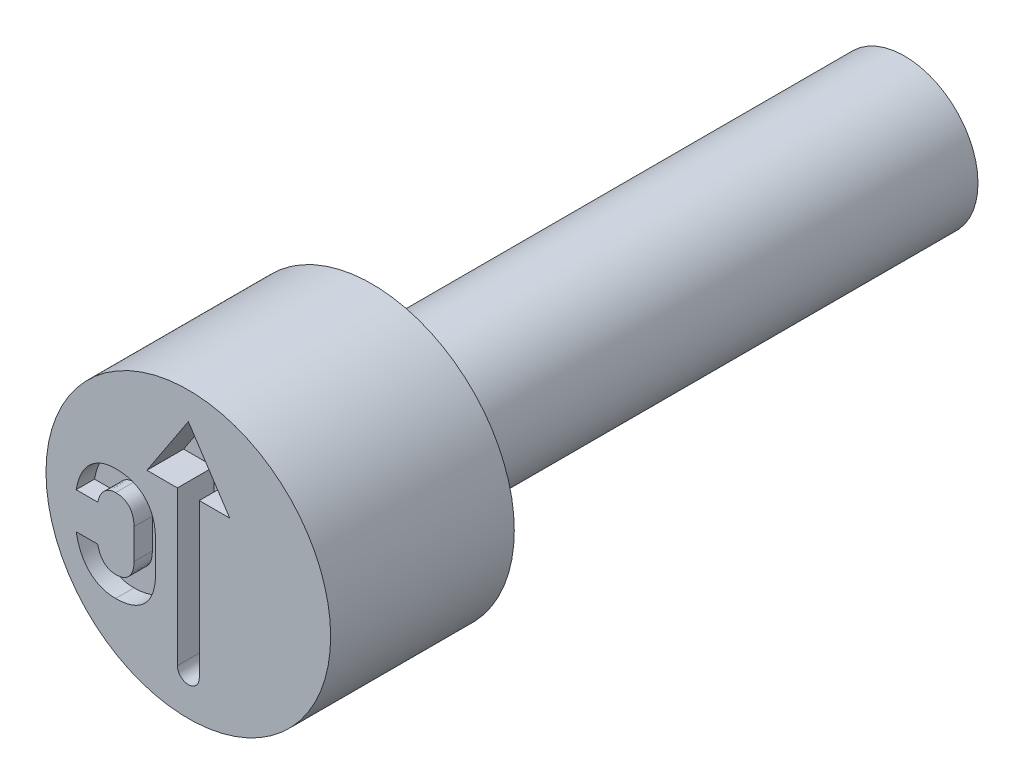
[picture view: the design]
ISO-10303-21;
HEADER;
FILE_DESCRIPTION(('STEP AP214'),'2;1');
FILE_NAME('part.step','',(''),(''),'','','');
FILE_SCHEMA(('AUTOMOTIVE_DESIGN { 1 0 10303 214 1 1 1 1 }'));
ENDSEC;
DATA;
#1=APPLICATION_CONTEXT('core data for automotive mechanical design processes');
#2=APPLICATION_PROTOCOL_DEFINITION('international standard','automotive_design',2000,#1);
#3=PRODUCT_CONTEXT('',#1,'mechanical');
#4=PRODUCT('Part','Part','',(#3));
#5=PRODUCT_RELATED_PRODUCT_CATEGORY('part','',(#4));
#6=PRODUCT_DEFINITION_FORMATION('','',#4);
#7=PRODUCT_DEFINITION_CONTEXT('part definition',#1,'design');
#8=PRODUCT_DEFINITION('design','',#6,#7);
#9=PRODUCT_DEFINITION_SHAPE('','',#8);
#10=(LENGTH_UNIT() NAMED_UNIT(*) SI_UNIT(.MILLI.,.METRE.));
#11=(NAMED_UNIT(*) PLANE_ANGLE_UNIT() SI_UNIT($,.RADIAN.));
#12=(NAMED_UNIT(*) SI_UNIT($,.STERADIAN.) SOLID_ANGLE_UNIT());
#13=UNCERTAINTY_MEASURE_WITH_UNIT(LENGTH_MEASURE(1.E-05),#10,'distance_accuracy_value','');
#14=(GEOMETRIC_REPRESENTATION_CONTEXT(3) GLOBAL_UNCERTAINTY_ASSIGNED_CONTEXT((#13)) GLOBAL_UNIT_ASSIGNED_CONTEXT((#10,
#11,#12)) REPRESENTATION_CONTEXT('',''));
#15=CARTESIAN_POINT('',(0.,0.,0.));
#16=DIRECTION('',(0.,0.,1.));
#17=DIRECTION('',(1.,0.,0.));
#18=AXIS2_PLACEMENT_3D('',#15,#16,#17);
#19=CARTESIAN_POINT('',(0.,0.799999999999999,-2.));
#20=DIRECTION('',(0.,0.,1.));
#21=DIRECTION('',(1.,0.,0.));
#22=AXIS2_PLACEMENT_3D('',#19,#20,#21);
#23=PLANE('',#22);
#24=CARTESIAN_POINT('',(0.,0.,-2.));
#25=DIRECTION('',(0.,0.,1.));
#26=DIRECTION('',(1.,0.,0.));
#27=AXIS2_PLACEMENT_3D('',#24,#25,#26);
#28=CIRCLE('',#27,1.55);
#29=CARTESIAN_POINT('',(1.55,0.,-2.));
#30=VERTEX_POINT('',#29);
#31=EDGE_CURVE('E11',#30,#30,#28,.T.);
#32=ORIENTED_EDGE('',*,*,#31,.F.);
#33=EDGE_LOOP('',(#32));
#34=FACE_BOUND('',#33,.T.);
#35=CARTESIAN_POINT('',(0.,0.,-2.));
#36=DIRECTION('',(0.,0.,1.));
#37=DIRECTION('',(1.,0.,0.));
#38=AXIS2_PLACEMENT_3D('',#35,#36,#37);
#39=CIRCLE('',#38,0.799999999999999);
#40=CARTESIAN_POINT('',(0.799999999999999,0.,-2.));
#41=VERTEX_POINT('',#40);
#42=EDGE_CURVE('E262',#41,#41,#39,.T.);
#43=ORIENTED_EDGE('',*,*,#42,.T.);
#44=EDGE_LOOP('',(#43));
#45=FACE_BOUND('',#44,.T.);
#46=ADVANCED_FACE('F34',(#34,#45),#23,.F.);
#47=CARTESIAN_POINT('',(0.,0.,-0.403888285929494));
#48=DIRECTION('',(0.,0.,1.));
#49=DIRECTION('',(1.,0.,0.));
#50=AXIS2_PLACEMENT_3D('',#47,#48,#49);
#51=CYLINDRICAL_SURFACE('',#50,1.55);
#52=CARTESIAN_POINT('',(0.,0.,0.));
#53=DIRECTION('',(0.,0.,1.));
#54=DIRECTION('',(1.,0.,0.));
#55=AXIS2_PLACEMENT_3D('',#52,#53,#54);
#56=CIRCLE('',#55,1.55);
#57=CARTESIAN_POINT('',(1.55,0.,0.));
#58=VERTEX_POINT('',#57);
#59=EDGE_CURVE('E41',#58,#58,#56,.T.);
#60=ORIENTED_EDGE('',*,*,#59,.F.);
#61=EDGE_LOOP('',(#60));
#62=FACE_BOUND('',#61,.T.);
#63=ORIENTED_EDGE('',*,*,#31,.T.);
#64=EDGE_LOOP('',(#63));
#65=FACE_BOUND('',#64,.T.);
#66=ADVANCED_FACE('F247',(#62,#65),#51,.T.);
#67=CARTESIAN_POINT('',(0.,1.55,0.));
#68=DIRECTION('',(0.,0.,-1.));
#69=DIRECTION('',(-1.,0.,0.));
#70=AXIS2_PLACEMENT_3D('',#67,#68,#69);
#71=PLANE('',#70);
#72=CARTESIAN_POINT('',(-0.791430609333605,-0.812471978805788,0.));
#73=CARTESIAN_POINT('',(-0.780258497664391,-0.812351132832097,0.));
#74=CARTESIAN_POINT('',(-0.758212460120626,-0.812112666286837,0.));
#75=CARTESIAN_POINT('',(-0.725795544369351,-0.809631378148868,0.));
#76=CARTESIAN_POINT('',(-0.694521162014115,-0.805483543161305,0.));
#77=CARTESIAN_POINT('',(-0.66455986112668,-0.799634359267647,0.));
#78=CARTESIAN_POINT('',(-0.635828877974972,-0.792255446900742,0.));
#79=CARTESIAN_POINT('',(-0.608205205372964,-0.783533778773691,0.));
#80=CARTESIAN_POINT('',(-0.581954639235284,-0.772736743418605,0.));
#81=CARTESIAN_POINT('',(-0.556822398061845,-0.760492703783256,0.));
#82=CARTESIAN_POINT('',(-0.53316239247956,-0.746634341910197,0.));
#83=CARTESIAN_POINT('',(-0.511024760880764,-0.731046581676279,0.));
#84=CARTESIAN_POINT('',(-0.490189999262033,-0.714218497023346,0.));
#85=CARTESIAN_POINT('',(-0.470816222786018,-0.695812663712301,0.));
#86=CARTESIAN_POINT('',(-0.452923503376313,-0.675936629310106,0.));
#87=CARTESIAN_POINT('',(-0.436410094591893,-0.65456836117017,0.));
#88=CARTESIAN_POINT('',(-0.421615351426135,-0.631571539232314,0.));
#89=CARTESIAN_POINT('',(-0.408081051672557,-0.607256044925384,0.));
#90=CARTESIAN_POINT('',(-0.396039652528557,-0.58155541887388,0.));
#91=CARTESIAN_POINT('',(-0.385876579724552,-0.55434699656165,0.));
#92=CARTESIAN_POINT('',(-0.377065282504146,-0.525931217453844,0.));
#93=CARTESIAN_POINT('',(-0.36969451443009,-0.496312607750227,0.));
#94=CARTESIAN_POINT('',(-0.364051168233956,-0.465356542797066,0.));
#95=CARTESIAN_POINT('',(-0.360289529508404,-0.433086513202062,0.));
#96=CARTESIAN_POINT('',(-0.357681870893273,-0.39947214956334,0.));
#97=CARTESIAN_POINT('',(-0.357466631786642,-0.376610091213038,0.));
#98=CARTESIAN_POINT('',(-0.357356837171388,-0.364948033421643,0.));
#99=B_SPLINE_CURVE_WITH_KNOTS('',3,(#72,#73,#74,#75,#76,#77,#78,#79,#80,#81,#82,#83,#84,#85,#86,
#87,#88,#89,#90,#91,#92,#93,#94,#95,#96,#97,#98),.UNSPECIFIED.,.F.,.F.,(4,1,1,1,1,1,1,1,1,1,1,1,
1,1,1,1,1,1,1,1,1,1,1,1,4),(0.,0.04725989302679,0.0932584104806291,0.137448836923,
0.180669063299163,0.222325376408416,0.262898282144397,0.303117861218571,0.342294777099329,
0.381096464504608,0.418984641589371,0.456742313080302,0.494310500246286,0.531916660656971,
0.569787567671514,0.608434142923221,0.647492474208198,0.687453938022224,0.728384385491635,
0.770272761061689,0.813266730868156,0.85743965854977,0.903297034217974,0.950671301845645,1.),.UNSPECIFIED.);
#100=CARTESIAN_POINT('',(-0.791430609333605,-0.812471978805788,0.));
#101=VERTEX_POINT('',#100);
#102=CARTESIAN_POINT('',(-0.357356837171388,-0.364948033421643,0.));
#103=VERTEX_POINT('',#102);
#104=EDGE_CURVE('E400',#101,#103,#99,.T.);
#105=ORIENTED_EDGE('',*,*,#104,.F.);
#106=CARTESIAN_POINT('',(-1.22134705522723,-0.397962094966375,0.));
#107=CARTESIAN_POINT('',(-1.2171676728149,-0.419166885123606,0.));
#108=CARTESIAN_POINT('',(-1.20904219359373,-0.460392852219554,0.));
#109=CARTESIAN_POINT('',(-1.19078283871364,-0.519101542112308,0.));
#110=CARTESIAN_POINT('',(-1.16828133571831,-0.573041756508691,0.));
#111=CARTESIAN_POINT('',(-1.14150329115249,-0.62213258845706,0.));
#112=CARTESIAN_POINT('',(-1.11028545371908,-0.665888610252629,0.));
#113=CARTESIAN_POINT('',(-1.07537476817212,-0.704473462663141,0.));
#114=CARTESIAN_POINT('',(-1.03647621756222,-0.737561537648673,0.));
#115=CARTESIAN_POINT('',(-0.993669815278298,-0.764820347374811,0.));
#116=CARTESIAN_POINT('',(-0.947448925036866,-0.786249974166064,0.));
#117=CARTESIAN_POINT('',(-0.898066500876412,-0.80129948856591,0.));
#118=CARTESIAN_POINT('',(-0.845777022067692,-0.811035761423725,0.));
#119=CARTESIAN_POINT('',(-0.809816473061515,-0.811986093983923,0.));
#120=CARTESIAN_POINT('',(-0.791430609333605,-0.812471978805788,0.));
#121=B_SPLINE_CURVE_WITH_KNOTS('',3,(#106,#107,#108,#109,#110,#111,#112,#113,#114,#115,#116,
#117,#118,#119,#120),.UNSPECIFIED.,.F.,.F.,(4,1,1,1,1,1,1,1,1,1,1,1,4),(0.,0.0988237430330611,
0.192131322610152,0.28071953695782,0.365844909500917,0.447392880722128,0.52606487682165,
0.603327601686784,0.680299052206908,0.757555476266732,0.835645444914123,0.915969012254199,1.),.UNSPECIFIED.);
#122=CARTESIAN_POINT('',(-1.22134705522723,-0.397962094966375,0.));
#123=VERTEX_POINT('',#122);
#124=EDGE_CURVE('E48',#123,#101,#121,.T.);
#125=ORIENTED_EDGE('',*,*,#124,.F.);
#126=DIRECTION('',(-1.,0.,0.));
#127=VECTOR('',#126,1.);
#128=CARTESIAN_POINT('',(-0.987069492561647,-0.397962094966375,0.));
#129=LINE('',#128,#127);
#130=CARTESIAN_POINT('',(-0.987069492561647,-0.397962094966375,0.));
#131=VERTEX_POINT('',#130);
#132=EDGE_CURVE('E185',#131,#123,#129,.T.);
#133=ORIENTED_EDGE('',*,*,#132,.F.);
#134=CARTESIAN_POINT('',(-0.791430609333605,-0.586264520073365,0.));
#135=CARTESIAN_POINT('',(-0.799513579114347,-0.585946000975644,0.));
#136=CARTESIAN_POINT('',(-0.815367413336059,-0.585321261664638,0.));
#137=CARTESIAN_POINT('',(-0.838528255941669,-0.581496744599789,0.));
#138=CARTESIAN_POINT('',(-0.86033493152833,-0.57444835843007,0.));
#139=CARTESIAN_POINT('',(-0.880934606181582,-0.564951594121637,0.));
#140=CARTESIAN_POINT('',(-0.900176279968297,-0.552681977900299,0.));
#141=CARTESIAN_POINT('',(-0.917511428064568,-0.537522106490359,0.));
#142=CARTESIAN_POINT('',(-0.933658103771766,-0.520265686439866,0.));
#143=CARTESIAN_POINT('',(-0.948029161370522,-0.500350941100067,0.));
#144=CARTESIAN_POINT('',(-0.960768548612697,-0.47806525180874,0.));
#145=CARTESIAN_POINT('',(-0.971422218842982,-0.453400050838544,0.));
#146=CARTESIAN_POINT('',(-0.980669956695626,-0.426630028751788,0.));
#147=CARTESIAN_POINT('',(-0.984892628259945,-0.407713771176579,0.));
#148=CARTESIAN_POINT('',(-0.987069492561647,-0.397962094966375,0.));
#149=B_SPLINE_CURVE_WITH_KNOTS('',3,(#134,#135,#136,#137,#138,#139,#140,#141,#142,#143,#144,
#145,#146,#147,#148),.UNSPECIFIED.,.F.,.F.,(4,1,1,1,1,1,1,1,1,1,1,1,4),(0.,0.0817564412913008,
0.160356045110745,0.236478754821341,0.312819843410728,0.389192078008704,0.466352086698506,
0.545094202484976,0.627698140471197,0.714093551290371,0.80415108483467,0.89903630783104,1.),.UNSPECIFIED.);
#150=CARTESIAN_POINT('',(-0.791430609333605,-0.586264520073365,0.));
#151=VERTEX_POINT('',#150);
#152=EDGE_CURVE('E188',#151,#131,#149,.T.);
#153=ORIENTED_EDGE('',*,*,#152,.F.);
#154=CARTESIAN_POINT('',(-0.591634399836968,-0.364948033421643,0.));
#155=CARTESIAN_POINT('',(-0.591898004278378,-0.376212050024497,0.));
#156=CARTESIAN_POINT('',(-0.592408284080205,-0.398016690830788,0.));
#157=CARTESIAN_POINT('',(-0.59682906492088,-0.429429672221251,0.));
#158=CARTESIAN_POINT('',(-0.604142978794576,-0.4583247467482,0.));
#159=CARTESIAN_POINT('',(-0.614290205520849,-0.484652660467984,0.));
#160=CARTESIAN_POINT('',(-0.62761931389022,-0.508037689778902,0.));
#161=CARTESIAN_POINT('',(-0.6434486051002,-0.528668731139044,0.));
#162=CARTESIAN_POINT('',(-0.661869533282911,-0.546495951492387,0.));
#163=CARTESIAN_POINT('',(-0.683168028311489,-0.561000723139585,0.));
#164=CARTESIAN_POINT('',(-0.706927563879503,-0.572346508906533,0.));
#165=CARTESIAN_POINT('',(-0.733057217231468,-0.580321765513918,0.));
#166=CARTESIAN_POINT('',(-0.76148736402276,-0.585328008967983,0.));
#167=CARTESIAN_POINT('',(-0.781219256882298,-0.585945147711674,0.));
#168=CARTESIAN_POINT('',(-0.791430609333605,-0.586264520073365,0.));
#169=B_SPLINE_CURVE_WITH_KNOTS('',3,(#154,#155,#156,#157,#158,#159,#160,#161,#162,#163,#164,
#165,#166,#167,#168),.UNSPECIFIED.,.F.,.F.,(4,1,1,1,1,1,1,1,1,1,1,1,4),(0.,0.0997433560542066,
0.193081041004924,0.28029932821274,0.363302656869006,0.442209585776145,0.517891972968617,
0.592965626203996,0.668275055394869,0.745143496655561,0.825309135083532,0.909596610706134,1.),.UNSPECIFIED.);
#170=CARTESIAN_POINT('',(-0.591634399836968,-0.364948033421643,0.));
#171=VERTEX_POINT('',#170);
#172=EDGE_CURVE('E348',#171,#151,#169,.T.);
#173=ORIENTED_EDGE('',*,*,#172,.F.);
#174=DIRECTION('',(0.,-1.,0.));
#175=VECTOR('',#174,1.);
#176=CARTESIAN_POINT('',(-0.591634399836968,-0.0357856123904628,0.));
#177=LINE('',#176,#175);
#178=CARTESIAN_POINT('',(-0.591634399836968,-0.0357856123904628,0.));
#179=VERTEX_POINT('',#178);
#180=EDGE_CURVE('E356',#179,#171,#177,.T.);
#181=ORIENTED_EDGE('',*,*,#180,.F.);
#182=CARTESIAN_POINT('',(-0.791430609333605,0.186264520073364,0.));
#183=CARTESIAN_POINT('',(-0.781226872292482,0.185907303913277,0.));
#184=CARTESIAN_POINT('',(-0.761523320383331,0.185217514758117,0.));
#185=CARTESIAN_POINT('',(-0.732979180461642,0.180723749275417,0.));
#186=CARTESIAN_POINT('',(-0.706978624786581,0.172258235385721,0.));
#187=CARTESIAN_POINT('',(-0.683158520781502,0.161027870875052,0.));
#188=CARTESIAN_POINT('',(-0.661879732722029,0.146482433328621,0.));
#189=CARTESIAN_POINT('',(-0.643370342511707,0.128650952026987,0.));
#190=CARTESIAN_POINT('',(-0.627621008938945,0.107775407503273,0.));
#191=CARTESIAN_POINT('',(-0.614349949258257,0.0842150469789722,0.));
#192=CARTESIAN_POINT('',(-0.604088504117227,0.0577700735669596,0.));
#193=CARTESIAN_POINT('',(-0.596868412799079,0.0287667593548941,0.));
#194=CARTESIAN_POINT('',(-0.592400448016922,-0.00271483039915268,0.));
#195=CARTESIAN_POINT('',(-0.591895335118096,-0.0245208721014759,0.));
#196=CARTESIAN_POINT('',(-0.591634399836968,-0.0357856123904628,0.));
#197=B_SPLINE_CURVE_WITH_KNOTS('',3,(#182,#183,#184,#185,#186,#187,#188,#189,#190,#191,#192,
#193,#194,#195,#196),.UNSPECIFIED.,.F.,.F.,(4,1,1,1,1,1,1,1,1,1,1,1,4),(0.,0.0902231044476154,
0.174222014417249,0.25444494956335,0.331160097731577,0.406319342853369,0.481243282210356,
0.557346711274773,0.636723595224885,0.719561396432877,0.807304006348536,0.900455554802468,1.),.UNSPECIFIED.);
#198=CARTESIAN_POINT('',(-0.791430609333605,0.186264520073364,0.));
#199=VERTEX_POINT('',#198);
#200=EDGE_CURVE('E362',#199,#179,#197,.T.);
#201=ORIENTED_EDGE('',*,*,#200,.F.);
#202=CARTESIAN_POINT('',(-0.987069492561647,-0.00179335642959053,0.));
#203=CARTESIAN_POINT('',(-0.984706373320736,0.00779221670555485,0.));
#204=CARTESIAN_POINT('',(-0.980107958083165,0.0264448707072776,0.));
#205=CARTESIAN_POINT('',(-0.970640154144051,0.0529798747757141,0.));
#206=CARTESIAN_POINT('',(-0.959874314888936,0.0775584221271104,0.));
#207=CARTESIAN_POINT('',(-0.946707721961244,0.0995949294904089,0.));
#208=CARTESIAN_POINT('',(-0.932374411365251,0.11962144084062,0.));
#209=CARTESIAN_POINT('',(-0.916209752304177,0.136971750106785,0.));
#210=CARTESIAN_POINT('',(-0.898567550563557,0.151933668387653,0.));
#211=CARTESIAN_POINT('',(-0.879584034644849,0.164308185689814,0.));
#212=CARTESIAN_POINT('',(-0.859310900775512,0.17439320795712,0.));
#213=CARTESIAN_POINT('',(-0.837655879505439,0.181067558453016,0.));
#214=CARTESIAN_POINT('',(-0.814917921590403,0.185425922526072,0.));
#215=CARTESIAN_POINT('',(-0.799358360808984,0.185981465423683,0.));
#216=CARTESIAN_POINT('',(-0.791430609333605,0.186264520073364,0.));
#217=B_SPLINE_CURVE_WITH_KNOTS('',3,(#202,#203,#204,#205,#206,#207,#208,#209,#210,#211,#212,
#213,#214,#215,#216),.UNSPECIFIED.,.F.,.F.,(4,1,1,1,1,1,1,1,1,1,1,1,4),(0.,0.100258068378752,
0.195093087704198,0.285925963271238,0.37244127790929,0.455447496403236,0.535743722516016,
0.612742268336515,0.689936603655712,0.765509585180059,0.842003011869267,0.919498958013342,1.),.UNSPECIFIED.);
#218=CARTESIAN_POINT('',(-0.987069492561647,-0.00179335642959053,0.));
#219=VERTEX_POINT('',#218);
#220=EDGE_CURVE('E367',#219,#199,#217,.T.);
#221=ORIENTED_EDGE('',*,*,#220,.F.);
#222=DIRECTION('',(1.,0.,0.));
#223=VECTOR('',#222,1.);
#224=CARTESIAN_POINT('',(-1.22134705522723,-0.00179335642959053,0.));
#225=LINE('',#224,#223);
#226=CARTESIAN_POINT('',(-1.22134705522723,-0.00179335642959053,0.));
#227=VERTEX_POINT('',#226);
#228=EDGE_CURVE('E375',#227,#219,#225,.T.);
#229=ORIENTED_EDGE('',*,*,#228,.F.);
#230=CARTESIAN_POINT('',(-0.791430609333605,0.412471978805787,0.));
#231=CARTESIAN_POINT('',(-0.809815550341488,0.411979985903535,0.));
#232=CARTESIAN_POINT('',(-0.84585461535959,0.411015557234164,0.));
#233=CARTESIAN_POINT('',(-0.89823459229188,0.401332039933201,0.));
#234=CARTESIAN_POINT('',(-0.947698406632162,0.386255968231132,0.));
#235=CARTESIAN_POINT('',(-0.9939569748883,0.364758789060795,0.));
#236=CARTESIAN_POINT('',(-1.03686547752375,0.337635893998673,0.));
#237=CARTESIAN_POINT('',(-1.07592155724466,0.304635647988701,0.));
#238=CARTESIAN_POINT('',(-1.11111207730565,0.266190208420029,0.));
#239=CARTESIAN_POINT('',(-1.14213327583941,0.222142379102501,0.));
#240=CARTESIAN_POINT('',(-1.16907351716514,0.173106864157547,0.));
#241=CARTESIAN_POINT('',(-1.19125174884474,0.11907771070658,0.));
#242=CARTESIAN_POINT('',(-1.2092538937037,0.060457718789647,0.));
#243=CARTESIAN_POINT('',(-1.2172439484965,0.0193279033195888,0.));
#244=CARTESIAN_POINT('',(-1.22134705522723,-0.00179335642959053,0.));
#245=B_SPLINE_CURVE_WITH_KNOTS('',3,(#230,#231,#232,#233,#234,#235,#236,#237,#238,#239,#240,
#241,#242,#243,#244),.UNSPECIFIED.,.F.,.F.,(4,1,1,1,1,1,1,1,1,1,1,1,4),(0.,0.0840057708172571,
0.164672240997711,0.242738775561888,0.319972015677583,0.397234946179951,0.474233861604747,
0.553133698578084,0.634960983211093,0.720060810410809,0.808478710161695,0.901648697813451,1.),.UNSPECIFIED.);
#246=CARTESIAN_POINT('',(-0.791430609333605,0.412471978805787,0.));
#247=VERTEX_POINT('',#246);
#248=EDGE_CURVE('E381',#247,#227,#245,.T.);
#249=ORIENTED_EDGE('',*,*,#248,.F.);
#250=CARTESIAN_POINT('',(-0.357356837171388,-0.0357856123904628,0.));
#251=CARTESIAN_POINT('',(-0.357466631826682,-0.0241235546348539,0.));
#252=CARTESIAN_POINT('',(-0.357681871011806,-0.00126149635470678,0.));
#253=CARTESIAN_POINT('',(-0.360289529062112,0.032352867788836,0.));
#254=CARTESIAN_POINT('',(-0.364051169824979,0.0646228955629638,0.));
#255=CARTESIAN_POINT('',(-0.369694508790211,0.0955789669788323,0.));
#256=CARTESIAN_POINT('',(-0.377065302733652,0.125197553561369,0.));
#257=CARTESIAN_POINT('',(-0.385876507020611,0.153613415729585,0.));
#258=CARTESIAN_POINT('',(-0.396039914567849,0.180821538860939,0.));
#259=CARTESIAN_POINT('',(-0.408080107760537,0.206523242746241,0.));
#260=CARTESIAN_POINT('',(-0.421618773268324,0.230834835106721,0.));
#261=CARTESIAN_POINT('',(-0.436397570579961,0.253845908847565,0.));
#262=CARTESIAN_POINT('',(-0.453006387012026,0.275210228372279,0.));
#263=CARTESIAN_POINT('',(-0.470729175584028,0.295319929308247,0.));
#264=CARTESIAN_POINT('',(-0.490200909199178,0.313720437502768,0.));
#265=CARTESIAN_POINT('',(-0.511024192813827,0.330554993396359,0.));
#266=CARTESIAN_POINT('',(-0.53315359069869,0.346164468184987,0.));
#267=CARTESIAN_POINT('',(-0.556890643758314,0.35994506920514,0.));
#268=CARTESIAN_POINT('',(-0.581878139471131,0.372572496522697,0.));
#269=CARTESIAN_POINT('',(-0.608264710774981,0.383198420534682,0.));
#270=CARTESIAN_POINT('',(-0.635774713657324,0.392337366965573,0.));
#271=CARTESIAN_POINT('',(-0.664568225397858,0.399609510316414,0.));
#272=CARTESIAN_POINT('',(-0.694518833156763,0.405490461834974,0.));
#273=CARTESIAN_POINT('',(-0.725796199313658,0.409629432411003,0.));
#274=CARTESIAN_POINT('',(-0.758212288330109,0.412113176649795,0.));
#275=CARTESIAN_POINT('',(-0.780258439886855,0.412351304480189,0.));
#276=CARTESIAN_POINT('',(-0.791430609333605,0.412471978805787,0.));
#277=B_SPLINE_CURVE_WITH_KNOTS('',3,(#250,#251,#252,#253,#254,#255,#256,#257,#258,#259,#260,
#261,#262,#263,#264,#265,#266,#267,#268,#269,#270,#271,#272,#273,#274,#275,#276),.UNSPECIFIED.,
.F.,.F.,(4,1,1,1,1,1,1,1,1,1,1,1,1,1,1,1,1,1,1,1,1,1,1,1,4),(0.,0.0493032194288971,
0.0966530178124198,0.142486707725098,0.186636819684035,0.229608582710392,0.271475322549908,
0.312384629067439,0.352325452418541,0.391363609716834,0.429990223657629,0.467841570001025,
0.505685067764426,0.543233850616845,0.580972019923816,0.618840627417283,0.657622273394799,
0.696931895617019,0.737130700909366,0.777789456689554,0.819424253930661,0.862622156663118,
0.906789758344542,0.952764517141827,1.),.UNSPECIFIED.);
#278=CARTESIAN_POINT('',(-0.357356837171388,-0.0357856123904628,0.));
#279=VERTEX_POINT('',#278);
#280=EDGE_CURVE('E386',#279,#247,#277,.T.);
#281=ORIENTED_EDGE('',*,*,#280,.F.);
#282=DIRECTION('',(0.,1.,0.));
#283=VECTOR('',#282,1.);
#284=CARTESIAN_POINT('',(-0.357356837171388,-0.364948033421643,0.));
#285=LINE('',#284,#283);
#286=EDGE_CURVE('E394',#103,#279,#285,.T.);
#287=ORIENTED_EDGE('',*,*,#286,.F.);
#288=EDGE_LOOP('',(#105,#125,#133,#153,#173,#181,#201,#221,#229,#249,#281,#287));
#289=FACE_BOUND('',#288,.T.);
#290=DIRECTION('',(0.,1.,0.));
#291=VECTOR('',#290,1.);
#292=CARTESIAN_POINT('',(0.119045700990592,0.566469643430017,0.));
#293=LINE('',#292,#291);
#294=CARTESIAN_POINT('',(0.119045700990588,-1.11010114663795,0.));
#295=VERTEX_POINT('',#294);
#296=CARTESIAN_POINT('',(0.119045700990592,0.566469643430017,0.));
#297=VERTEX_POINT('',#296);
#298=EDGE_CURVE('E300',#295,#297,#293,.T.);
#299=ORIENTED_EDGE('',*,*,#298,.F.);
#300=CARTESIAN_POINT('',(1.02140308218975E-13,-1.11010114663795,0.));
#301=DIRECTION('',(0.,0.,1.));
#302=DIRECTION('',(1.,0.,0.));
#303=AXIS2_PLACEMENT_3D('',#300,#301,#302);
#304=CIRCLE('',#303,0.119045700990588);
#305=CARTESIAN_POINT('',(-0.119045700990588,-1.11010114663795,0.));
#306=VERTEX_POINT('',#305);
#307=EDGE_CURVE('E56',#306,#295,#304,.T.);
#308=ORIENTED_EDGE('',*,*,#307,.F.);
#309=DIRECTION('',(0.,-1.,0.));
#310=VECTOR('',#309,1.);
#311=CARTESIAN_POINT('',(-0.119045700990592,0.566469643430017,0.));
#312=LINE('',#311,#310);
#313=CARTESIAN_POINT('',(-0.119045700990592,0.566469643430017,0.));
#314=VERTEX_POINT('',#313);
#315=EDGE_CURVE('E284',#314,#306,#312,.T.);
#316=ORIENTED_EDGE('',*,*,#315,.F.);
#317=DIRECTION('',(1.,0.,0.));
#318=VECTOR('',#317,1.);
#319=CARTESIAN_POINT('',(-0.451198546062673,0.566469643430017,0.));
#320=LINE('',#319,#318);
#321=CARTESIAN_POINT('',(-0.451198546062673,0.566469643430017,0.));
#322=VERTEX_POINT('',#321);
#323=EDGE_CURVE('E288',#322,#314,#320,.T.);
#324=ORIENTED_EDGE('',*,*,#323,.F.);
#325=DIRECTION('',(-0.550159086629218,-0.835059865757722,0.));
#326=VECTOR('',#325,1.);
#327=CARTESIAN_POINT('',(0.,1.25132209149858,0.));
#328=LINE('',#327,#326);
#329=CARTESIAN_POINT('',(0.,1.25132209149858,0.));
#330=VERTEX_POINT('',#329);
#331=EDGE_CURVE('E291',#330,#322,#328,.T.);
#332=ORIENTED_EDGE('',*,*,#331,.F.);
#333=DIRECTION('',(-0.550159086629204,0.835059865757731,0.));
#334=VECTOR('',#333,1.);
#335=CARTESIAN_POINT('',(0.,1.25132209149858,0.));
#336=LINE('',#335,#334);
#337=CARTESIAN_POINT('',(0.451198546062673,0.566469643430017,0.));
#338=VERTEX_POINT('',#337);
#339=EDGE_CURVE('E294',#338,#330,#336,.T.);
#340=ORIENTED_EDGE('',*,*,#339,.F.);
#341=DIRECTION('',(1.,0.,0.));
#342=VECTOR('',#341,1.);
#343=CARTESIAN_POINT('',(0.451198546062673,0.566469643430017,0.));
#344=LINE('',#343,#342);
#345=EDGE_CURVE('E297',#297,#338,#344,.T.);
#346=ORIENTED_EDGE('',*,*,#345,.F.);
#347=EDGE_LOOP('',(#299,#308,#316,#324,#332,#340,#346));
#348=FACE_BOUND('',#347,.T.);
#349=ORIENTED_EDGE('',*,*,#59,.T.);
#350=EDGE_LOOP('',(#349));
#351=FACE_BOUND('',#350,.T.);
#352=ADVANCED_FACE('F244',(#289,#348,#351),#71,.F.);
#353=CARTESIAN_POINT('',(0.,0.,-7.8));
#354=DIRECTION('',(0.,0.,1.));
#355=DIRECTION('',(1.,0.,0.));
#356=AXIS2_PLACEMENT_3D('',#353,#354,#355);
#357=PLANE('',#356);
#358=CARTESIAN_POINT('',(0.,0.,-7.8));
#359=DIRECTION('',(0.,0.,1.));
#360=DIRECTION('',(1.,0.,0.));
#361=AXIS2_PLACEMENT_3D('',#358,#359,#360);
#362=CIRCLE('',#361,0.799999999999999);
#363=CARTESIAN_POINT('',(0.799999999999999,0.,-7.8));
#364=VERTEX_POINT('',#363);
#365=EDGE_CURVE('E263',#364,#364,#362,.T.);
#366=ORIENTED_EDGE('',*,*,#365,.F.);
#367=EDGE_LOOP('',(#366));
#368=FACE_BOUND('',#367,.T.);
#369=ADVANCED_FACE('F240',(#368),#357,.F.);
#370=CARTESIAN_POINT('',(0.,0.,-0.403888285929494));
#371=DIRECTION('',(0.,0.,1.));
#372=DIRECTION('',(1.,0.,0.));
#373=AXIS2_PLACEMENT_3D('',#370,#371,#372);
#374=CYLINDRICAL_SURFACE('',#373,0.799999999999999);
#375=ORIENTED_EDGE('',*,*,#42,.F.);
#376=EDGE_LOOP('',(#375));
#377=FACE_BOUND('',#376,.T.);
#378=ORIENTED_EDGE('',*,*,#365,.T.);
#379=EDGE_LOOP('',(#378));
#380=FACE_BOUND('',#379,.T.);
#381=ADVANCED_FACE('F237',(#377,#380),#374,.T.);
#382=CARTESIAN_POINT('',(1.02140308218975E-13,-1.11010114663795,-0.4));
#383=DIRECTION('',(0.,0.,1.));
#384=DIRECTION('',(1.,0.,0.));
#385=AXIS2_PLACEMENT_3D('',#382,#383,#384);
#386=CYLINDRICAL_SURFACE('',#385,0.119045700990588);
#387=ORIENTED_EDGE('',*,*,#307,.T.);
#388=DIRECTION('',(0.,0.,1.));
#389=VECTOR('',#388,1.);
#390=CARTESIAN_POINT('',(0.119045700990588,-1.11010114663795,-0.4));
#391=LINE('',#390,#389);
#392=CARTESIAN_POINT('',(0.119045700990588,-1.11010114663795,-0.4));
#393=VERTEX_POINT('',#392);
#394=EDGE_CURVE('E271',#393,#295,#391,.T.);
#395=ORIENTED_EDGE('',*,*,#394,.F.);
#396=CARTESIAN_POINT('',(1.02140308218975E-13,-1.11010114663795,-0.4));
#397=DIRECTION('',(0.,0.,1.));
#398=DIRECTION('',(1.,0.,0.));
#399=AXIS2_PLACEMENT_3D('',#396,#397,#398);
#400=CIRCLE('',#399,0.119045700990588);
#401=CARTESIAN_POINT('',(-0.119045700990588,-1.11010114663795,-0.4));
#402=VERTEX_POINT('',#401);
#403=EDGE_CURVE('E287',#402,#393,#400,.T.);
#404=ORIENTED_EDGE('',*,*,#403,.F.);
#405=DIRECTION('',(0.,0.,1.));
#406=VECTOR('',#405,1.);
#407=CARTESIAN_POINT('',(-0.119045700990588,-1.11010114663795,-0.4));
#408=LINE('',#407,#406);
#409=EDGE_CURVE('E264',#402,#306,#408,.T.);
#410=ORIENTED_EDGE('',*,*,#409,.T.);
#411=EDGE_LOOP('',(#387,#395,#404,#410));
#412=FACE_BOUND('',#411,.T.);
#413=ADVANCED_FACE('F215',(#412),#386,.F.);
#414=CARTESIAN_POINT('',(-0.119045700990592,0.566469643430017,-0.4));
#415=DIRECTION('',(-1.,0.,0.));
#416=DIRECTION('',(0.,-1.,0.));
#417=AXIS2_PLACEMENT_3D('',#414,#415,#416);
#418=PLANE('',#417);
#419=ORIENTED_EDGE('',*,*,#315,.T.);
#420=ORIENTED_EDGE('',*,*,#409,.F.);
#421=DIRECTION('',(0.,-1.,0.));
#422=VECTOR('',#421,1.);
#423=CARTESIAN_POINT('',(-0.119045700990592,0.566469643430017,-0.4));
#424=LINE('',#423,#422);
#425=CARTESIAN_POINT('',(-0.119045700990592,0.566469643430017,-0.4));
#426=VERTEX_POINT('',#425);
#427=EDGE_CURVE('E275',#426,#402,#424,.T.);
#428=ORIENTED_EDGE('',*,*,#427,.F.);
#429=DIRECTION('',(0.,0.,1.));
#430=VECTOR('',#429,1.);
#431=CARTESIAN_POINT('',(-0.119045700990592,0.566469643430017,-0.4));
#432=LINE('',#431,#430);
#433=EDGE_CURVE('E268',#426,#314,#432,.T.);
#434=ORIENTED_EDGE('',*,*,#433,.T.);
#435=EDGE_LOOP('',(#419,#420,#428,#434));
#436=FACE_BOUND('',#435,.T.);
#437=ADVANCED_FACE('F211',(#436),#418,.F.);
#438=CARTESIAN_POINT('',(-0.451198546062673,0.566469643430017,-0.4));
#439=DIRECTION('',(0.,-1.,0.));
#440=DIRECTION('',(0.,0.,-1.));
#441=AXIS2_PLACEMENT_3D('',#438,#439,#440);
#442=PLANE('',#441);
#443=ORIENTED_EDGE('',*,*,#323,.T.);
#444=ORIENTED_EDGE('',*,*,#433,.F.);
#445=DIRECTION('',(1.,0.,0.));
#446=VECTOR('',#445,1.);
#447=CARTESIAN_POINT('',(-0.451198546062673,0.566469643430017,-0.4));
#448=LINE('',#447,#446);
#449=CARTESIAN_POINT('',(-0.451198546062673,0.566469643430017,-0.4));
#450=VERTEX_POINT('',#449);
#451=EDGE_CURVE('E307',#450,#426,#448,.T.);
#452=ORIENTED_EDGE('',*,*,#451,.F.);
#453=DIRECTION('',(0.,0.,1.));
#454=VECTOR('',#453,1.);
#455=CARTESIAN_POINT('',(-0.451198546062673,0.566469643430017,-0.4));
#456=LINE('',#455,#454);
#457=EDGE_CURVE('E281',#450,#322,#456,.T.);
#458=ORIENTED_EDGE('',*,*,#457,.T.);
#459=EDGE_LOOP('',(#443,#444,#452,#458));
#460=FACE_BOUND('',#459,.T.);
#461=ADVANCED_FACE('F214',(#460),#442,.F.);
#462=CARTESIAN_POINT('',(0.,1.25132209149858,-0.4));
#463=DIRECTION('',(-0.835059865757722,0.550159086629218,0.));
#464=DIRECTION('',(-0.550159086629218,-0.835059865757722,0.));
#465=AXIS2_PLACEMENT_3D('',#462,#463,#464);
#466=PLANE('',#465);
#467=ORIENTED_EDGE('',*,*,#331,.T.);
#468=ORIENTED_EDGE('',*,*,#457,.F.);
#469=DIRECTION('',(-0.550159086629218,-0.835059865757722,0.));
#470=VECTOR('',#469,1.);
#471=CARTESIAN_POINT('',(0.,1.25132209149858,-0.4));
#472=LINE('',#471,#470);
#473=CARTESIAN_POINT('',(0.,1.25132209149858,-0.4));
#474=VERTEX_POINT('',#473);
#475=EDGE_CURVE('E310',#474,#450,#472,.T.);
#476=ORIENTED_EDGE('',*,*,#475,.F.);
#477=DIRECTION('',(0.,0.,1.));
#478=VECTOR('',#477,1.);
#479=CARTESIAN_POINT('',(0.,1.25132209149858,-0.4));
#480=LINE('',#479,#478);
#481=EDGE_CURVE('E279',#474,#330,#480,.T.);
#482=ORIENTED_EDGE('',*,*,#481,.T.);
#483=EDGE_LOOP('',(#467,#468,#476,#482));
#484=FACE_BOUND('',#483,.T.);
#485=ADVANCED_FACE('F219',(#484),#466,.F.);
#486=CARTESIAN_POINT('',(0.,1.25132209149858,-0.4));
#487=DIRECTION('',(0.835059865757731,0.550159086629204,0.));
#488=DIRECTION('',(-0.550159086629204,0.835059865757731,0.));
#489=AXIS2_PLACEMENT_3D('',#486,#487,#488);
#490=PLANE('',#489);
#491=ORIENTED_EDGE('',*,*,#339,.T.);
#492=ORIENTED_EDGE('',*,*,#481,.F.);
#493=DIRECTION('',(-0.550159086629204,0.835059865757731,0.));
#494=VECTOR('',#493,1.);
#495=CARTESIAN_POINT('',(0.,1.25132209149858,-0.4));
#496=LINE('',#495,#494);
#497=CARTESIAN_POINT('',(0.451198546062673,0.566469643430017,-0.4));
#498=VERTEX_POINT('',#497);
#499=EDGE_CURVE('E313',#498,#474,#496,.T.);
#500=ORIENTED_EDGE('',*,*,#499,.F.);
#501=DIRECTION('',(0.,0.,1.));
#502=VECTOR('',#501,1.);
#503=CARTESIAN_POINT('',(0.451198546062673,0.566469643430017,-0.4));
#504=LINE('',#503,#502);
#505=EDGE_CURVE('E277',#498,#338,#504,.T.);
#506=ORIENTED_EDGE('',*,*,#505,.T.);
#507=EDGE_LOOP('',(#491,#492,#500,#506));
#508=FACE_BOUND('',#507,.T.);
#509=ADVANCED_FACE('F223',(#508),#490,.F.);
#510=CARTESIAN_POINT('',(0.451198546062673,0.566469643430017,-0.4));
#511=DIRECTION('',(0.,-1.,0.));
#512=DIRECTION('',(0.,0.,-1.));
#513=AXIS2_PLACEMENT_3D('',#510,#511,#512);
#514=PLANE('',#513);
#515=ORIENTED_EDGE('',*,*,#345,.T.);
#516=ORIENTED_EDGE('',*,*,#505,.F.);
#517=DIRECTION('',(1.,0.,0.));
#518=VECTOR('',#517,1.);
#519=CARTESIAN_POINT('',(0.451198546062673,0.566469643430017,-0.4));
#520=LINE('',#519,#518);
#521=CARTESIAN_POINT('',(0.119045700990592,0.566469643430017,-0.4));
#522=VERTEX_POINT('',#521);
#523=EDGE_CURVE('E316',#522,#498,#520,.T.);
#524=ORIENTED_EDGE('',*,*,#523,.F.);
#525=DIRECTION('',(0.,0.,1.));
#526=VECTOR('',#525,1.);
#527=CARTESIAN_POINT('',(0.119045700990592,0.566469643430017,-0.4));
#528=LINE('',#527,#526);
#529=EDGE_CURVE('E274',#522,#297,#528,.T.);
#530=ORIENTED_EDGE('',*,*,#529,.T.);
#531=EDGE_LOOP('',(#515,#516,#524,#530));
#532=FACE_BOUND('',#531,.T.);
#533=ADVANCED_FACE('F227',(#532),#514,.F.);
#534=CARTESIAN_POINT('',(0.119045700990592,0.566469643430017,-0.4));
#535=DIRECTION('',(1.,0.,0.));
#536=DIRECTION('',(0.,1.,0.));
#537=AXIS2_PLACEMENT_3D('',#534,#535,#536);
#538=PLANE('',#537);
#539=ORIENTED_EDGE('',*,*,#298,.T.);
#540=ORIENTED_EDGE('',*,*,#529,.F.);
#541=DIRECTION('',(0.,1.,0.));
#542=VECTOR('',#541,1.);
#543=CARTESIAN_POINT('',(0.119045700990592,0.566469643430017,-0.4));
#544=LINE('',#543,#542);
#545=EDGE_CURVE('E319',#393,#522,#544,.T.);
#546=ORIENTED_EDGE('',*,*,#545,.F.);
#547=ORIENTED_EDGE('',*,*,#394,.T.);
#548=EDGE_LOOP('',(#539,#540,#546,#547));
#549=FACE_BOUND('',#548,.T.);
#550=ADVANCED_FACE('F209',(#549),#538,.F.);
#551=CARTESIAN_POINT('',(1.02140308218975E-13,-1.11010114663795,-0.4));
#552=DIRECTION('',(0.,0.,1.));
#553=DIRECTION('',(1.,0.,0.));
#554=AXIS2_PLACEMENT_3D('',#551,#552,#553);
#555=PLANE('',#554);
#556=ORIENTED_EDGE('',*,*,#403,.T.);
#557=ORIENTED_EDGE('',*,*,#545,.T.);
#558=ORIENTED_EDGE('',*,*,#523,.T.);
#559=ORIENTED_EDGE('',*,*,#499,.T.);
#560=ORIENTED_EDGE('',*,*,#475,.T.);
#561=ORIENTED_EDGE('',*,*,#451,.T.);
#562=ORIENTED_EDGE('',*,*,#427,.T.);
#563=EDGE_LOOP('',(#556,#557,#558,#559,#560,#561,#562));
#564=FACE_BOUND('',#563,.T.);
#565=ADVANCED_FACE('F205',(#564),#555,.T.);
#566=CARTESIAN_POINT('',(-1.22134705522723,-0.397962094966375,-0.2));
#567=CARTESIAN_POINT('',(-1.2171676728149,-0.419166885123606,-0.2));
#568=CARTESIAN_POINT('',(-1.20904219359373,-0.460392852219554,-0.2));
#569=CARTESIAN_POINT('',(-1.19078283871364,-0.519101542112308,-0.2));
#570=CARTESIAN_POINT('',(-1.16828133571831,-0.573041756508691,-0.2));
#571=CARTESIAN_POINT('',(-1.14150329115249,-0.62213258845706,-0.2));
#572=CARTESIAN_POINT('',(-1.11028545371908,-0.665888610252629,-0.2));
#573=CARTESIAN_POINT('',(-1.07537476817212,-0.704473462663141,-0.2));
#574=CARTESIAN_POINT('',(-1.03647621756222,-0.737561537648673,-0.2));
#575=CARTESIAN_POINT('',(-0.993669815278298,-0.764820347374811,-0.2));
#576=CARTESIAN_POINT('',(-0.947448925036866,-0.786249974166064,-0.2));
#577=CARTESIAN_POINT('',(-0.898066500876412,-0.80129948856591,-0.2));
#578=CARTESIAN_POINT('',(-0.845777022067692,-0.811035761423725,-0.2));
#579=CARTESIAN_POINT('',(-0.809816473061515,-0.811986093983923,-0.2));
#580=CARTESIAN_POINT('',(-0.791430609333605,-0.812471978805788,-0.2));
#581=B_SPLINE_CURVE_WITH_KNOTS('',3,(#566,#567,#568,#569,#570,#571,#572,#573,#574,#575,#576,
#577,#578,#579,#580),.UNSPECIFIED.,.F.,.F.,(4,1,1,1,1,1,1,1,1,1,1,1,4),(0.,0.0988237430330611,
0.192131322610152,0.28071953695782,0.365844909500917,0.447392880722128,0.52606487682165,
0.603327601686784,0.680299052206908,0.757555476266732,0.835645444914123,0.915969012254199,1.),.UNSPECIFIED.);
#582=DIRECTION('',(0.,0.,1.));
#583=VECTOR('',#582,1.);
#584=SURFACE_OF_LINEAR_EXTRUSION('',#581,#583);
#585=ORIENTED_EDGE('',*,*,#124,.T.);
#586=DIRECTION('',(0.,0.,1.));
#587=VECTOR('',#586,1.);
#588=CARTESIAN_POINT('',(-0.791430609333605,-0.812471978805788,-0.2));
#589=LINE('',#588,#587);
#590=CARTESIAN_POINT('',(-0.791430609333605,-0.812471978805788,-0.2));
#591=VERTEX_POINT('',#590);
#592=EDGE_CURVE('E162',#591,#101,#589,.T.);
#593=ORIENTED_EDGE('',*,*,#592,.F.);
#594=CARTESIAN_POINT('',(-1.22134705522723,-0.397962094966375,-0.2));
#595=VERTEX_POINT('',#594);
#596=EDGE_CURVE('E166',#595,#591,#581,.T.);
#597=ORIENTED_EDGE('',*,*,#596,.F.);
#598=DIRECTION('',(0.,0.,1.));
#599=VECTOR('',#598,1.);
#600=CARTESIAN_POINT('',(-1.22134705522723,-0.397962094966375,-0.2));
#601=LINE('',#600,#599);
#602=EDGE_CURVE('E304',#595,#123,#601,.T.);
#603=ORIENTED_EDGE('',*,*,#602,.T.);
#604=EDGE_LOOP('',(#585,#593,#597,#603));
#605=FACE_BOUND('',#604,.T.);
#606=ADVANCED_FACE('F164',(#605),#584,.F.);
#607=CARTESIAN_POINT('',(-0.987069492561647,-0.397962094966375,-0.2));
#608=DIRECTION('',(0.,1.,0.));
#609=DIRECTION('',(0.,0.,1.));
#610=AXIS2_PLACEMENT_3D('',#607,#608,#609);
#611=PLANE('',#610);
#612=ORIENTED_EDGE('',*,*,#132,.T.);
#613=ORIENTED_EDGE('',*,*,#602,.F.);
#614=DIRECTION('',(-1.,0.,0.));
#615=VECTOR('',#614,1.);
#616=CARTESIAN_POINT('',(-0.987069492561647,-0.397962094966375,-0.2));
#617=LINE('',#616,#615);
#618=CARTESIAN_POINT('',(-0.987069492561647,-0.397962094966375,-0.2));
#619=VERTEX_POINT('',#618);
#620=EDGE_CURVE('E172',#619,#595,#617,.T.);
#621=ORIENTED_EDGE('',*,*,#620,.F.);
#622=DIRECTION('',(0.,0.,1.));
#623=VECTOR('',#622,1.);
#624=CARTESIAN_POINT('',(-0.987069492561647,-0.397962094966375,-0.2));
#625=LINE('',#624,#623);
#626=EDGE_CURVE('E341',#619,#131,#625,.T.);
#627=ORIENTED_EDGE('',*,*,#626,.T.);
#628=EDGE_LOOP('',(#612,#613,#621,#627));
#629=FACE_BOUND('',#628,.T.);
#630=ADVANCED_FACE('F204',(#629),#611,.F.);
#631=CARTESIAN_POINT('',(-0.791430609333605,-0.586264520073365,-0.2));
#632=CARTESIAN_POINT('',(-0.799513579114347,-0.585946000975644,-0.2));
#633=CARTESIAN_POINT('',(-0.815367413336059,-0.585321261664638,-0.2));
#634=CARTESIAN_POINT('',(-0.838528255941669,-0.581496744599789,-0.2));
#635=CARTESIAN_POINT('',(-0.86033493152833,-0.57444835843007,-0.2));
#636=CARTESIAN_POINT('',(-0.880934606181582,-0.564951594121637,-0.2));
#637=CARTESIAN_POINT('',(-0.900176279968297,-0.552681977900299,-0.2));
#638=CARTESIAN_POINT('',(-0.917511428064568,-0.537522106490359,-0.2));
#639=CARTESIAN_POINT('',(-0.933658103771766,-0.520265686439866,-0.2));
#640=CARTESIAN_POINT('',(-0.948029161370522,-0.500350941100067,-0.2));
#641=CARTESIAN_POINT('',(-0.960768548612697,-0.47806525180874,-0.2));
#642=CARTESIAN_POINT('',(-0.971422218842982,-0.453400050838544,-0.2));
#643=CARTESIAN_POINT('',(-0.980669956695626,-0.426630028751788,-0.2));
#644=CARTESIAN_POINT('',(-0.984892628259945,-0.407713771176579,-0.2));
#645=CARTESIAN_POINT('',(-0.987069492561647,-0.397962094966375,-0.2));
#646=B_SPLINE_CURVE_WITH_KNOTS('',3,(#631,#632,#633,#634,#635,#636,#637,#638,#639,#640,#641,
#642,#643,#644,#645),.UNSPECIFIED.,.F.,.F.,(4,1,1,1,1,1,1,1,1,1,1,1,4),(0.,0.0817564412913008,
0.160356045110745,0.236478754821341,0.312819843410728,0.389192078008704,0.466352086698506,
0.545094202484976,0.627698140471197,0.714093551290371,0.80415108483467,0.89903630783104,1.),.UNSPECIFIED.);
#647=DIRECTION('',(0.,0.,1.));
#648=VECTOR('',#647,1.);
#649=SURFACE_OF_LINEAR_EXTRUSION('',#646,#648);
#650=ORIENTED_EDGE('',*,*,#152,.T.);
#651=ORIENTED_EDGE('',*,*,#626,.F.);
#652=CARTESIAN_POINT('',(-0.791430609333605,-0.586264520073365,-0.2));
#653=VERTEX_POINT('',#652);
#654=EDGE_CURVE('E414',#653,#619,#646,.T.);
#655=ORIENTED_EDGE('',*,*,#654,.F.);
#656=DIRECTION('',(0.,0.,1.));
#657=VECTOR('',#656,1.);
#658=CARTESIAN_POINT('',(-0.791430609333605,-0.586264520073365,-0.2));
#659=LINE('',#658,#657);
#660=EDGE_CURVE('E339',#653,#151,#659,.T.);
#661=ORIENTED_EDGE('',*,*,#660,.T.);
#662=EDGE_LOOP('',(#650,#651,#655,#661));
#663=FACE_BOUND('',#662,.T.);
#664=ADVANCED_FACE('F428',(#663),#649,.F.);
#665=CARTESIAN_POINT('',(-0.591634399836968,-0.364948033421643,-0.2));
#666=CARTESIAN_POINT('',(-0.591898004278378,-0.376212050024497,-0.2));
#667=CARTESIAN_POINT('',(-0.592408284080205,-0.398016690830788,-0.2));
#668=CARTESIAN_POINT('',(-0.59682906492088,-0.429429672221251,-0.2));
#669=CARTESIAN_POINT('',(-0.604142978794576,-0.4583247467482,-0.2));
#670=CARTESIAN_POINT('',(-0.614290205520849,-0.484652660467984,-0.2));
#671=CARTESIAN_POINT('',(-0.62761931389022,-0.508037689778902,-0.2));
#672=CARTESIAN_POINT('',(-0.6434486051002,-0.528668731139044,-0.2));
#673=CARTESIAN_POINT('',(-0.661869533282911,-0.546495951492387,-0.2));
#674=CARTESIAN_POINT('',(-0.683168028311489,-0.561000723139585,-0.2));
#675=CARTESIAN_POINT('',(-0.706927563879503,-0.572346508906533,-0.2));
#676=CARTESIAN_POINT('',(-0.733057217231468,-0.580321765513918,-0.2));
#677=CARTESIAN_POINT('',(-0.76148736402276,-0.585328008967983,-0.2));
#678=CARTESIAN_POINT('',(-0.781219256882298,-0.585945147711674,-0.2));
#679=CARTESIAN_POINT('',(-0.791430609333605,-0.586264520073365,-0.2));
#680=B_SPLINE_CURVE_WITH_KNOTS('',3,(#665,#666,#667,#668,#669,#670,#671,#672,#673,#674,#675,
#676,#677,#678,#679),.UNSPECIFIED.,.F.,.F.,(4,1,1,1,1,1,1,1,1,1,1,1,4),(0.,0.0997433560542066,
0.193081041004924,0.28029932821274,0.363302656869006,0.442209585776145,0.517891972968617,
0.592965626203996,0.668275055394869,0.745143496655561,0.825309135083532,0.909596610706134,1.),.UNSPECIFIED.);
#681=DIRECTION('',(0.,0.,1.));
#682=VECTOR('',#681,1.);
#683=SURFACE_OF_LINEAR_EXTRUSION('',#680,#682);
#684=ORIENTED_EDGE('',*,*,#172,.T.);
#685=ORIENTED_EDGE('',*,*,#660,.F.);
#686=CARTESIAN_POINT('',(-0.591634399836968,-0.364948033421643,-0.2));
#687=VERTEX_POINT('',#686);
#688=EDGE_CURVE('E419',#687,#653,#680,.T.);
#689=ORIENTED_EDGE('',*,*,#688,.F.);
#690=DIRECTION('',(0.,0.,1.));
#691=VECTOR('',#690,1.);
#692=CARTESIAN_POINT('',(-0.591634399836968,-0.364948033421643,-0.2));
#693=LINE('',#692,#691);
#694=EDGE_CURVE('E337',#687,#171,#693,.T.);
#695=ORIENTED_EDGE('',*,*,#694,.T.);
#696=EDGE_LOOP('',(#684,#685,#689,#695));
#697=FACE_BOUND('',#696,.T.);
#698=ADVANCED_FACE('F432',(#697),#683,.F.);
#699=CARTESIAN_POINT('',(-0.591634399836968,-0.0357856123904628,-0.2));
#700=DIRECTION('',(-1.,0.,0.));
#701=DIRECTION('',(0.,0.,1.));
#702=AXIS2_PLACEMENT_3D('',#699,#700,#701);
#703=PLANE('',#702);
#704=ORIENTED_EDGE('',*,*,#180,.T.);
#705=ORIENTED_EDGE('',*,*,#694,.F.);
#706=DIRECTION('',(0.,-1.,0.));
#707=VECTOR('',#706,1.);
#708=CARTESIAN_POINT('',(-0.591634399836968,-0.0357856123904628,-0.2));
#709=LINE('',#708,#707);
#710=CARTESIAN_POINT('',(-0.591634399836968,-0.0357856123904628,-0.2));
#711=VERTEX_POINT('',#710);
#712=EDGE_CURVE('E455',#711,#687,#709,.T.);
#713=ORIENTED_EDGE('',*,*,#712,.F.);
#714=DIRECTION('',(0.,0.,1.));
#715=VECTOR('',#714,1.);
#716=CARTESIAN_POINT('',(-0.591634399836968,-0.0357856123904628,-0.2));
#717=LINE('',#716,#715);
#718=EDGE_CURVE('E335',#711,#179,#717,.T.);
#719=ORIENTED_EDGE('',*,*,#718,.T.);
#720=EDGE_LOOP('',(#704,#705,#713,#719));
#721=FACE_BOUND('',#720,.T.);
#722=ADVANCED_FACE('F437',(#721),#703,.F.);
#723=CARTESIAN_POINT('',(-0.791430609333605,0.186264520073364,-0.2));
#724=CARTESIAN_POINT('',(-0.781226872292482,0.185907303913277,-0.2));
#725=CARTESIAN_POINT('',(-0.761523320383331,0.185217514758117,-0.2));
#726=CARTESIAN_POINT('',(-0.732979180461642,0.180723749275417,-0.2));
#727=CARTESIAN_POINT('',(-0.706978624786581,0.172258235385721,-0.2));
#728=CARTESIAN_POINT('',(-0.683158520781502,0.161027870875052,-0.2));
#729=CARTESIAN_POINT('',(-0.661879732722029,0.146482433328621,-0.2));
#730=CARTESIAN_POINT('',(-0.643370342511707,0.128650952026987,-0.2));
#731=CARTESIAN_POINT('',(-0.627621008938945,0.107775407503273,-0.2));
#732=CARTESIAN_POINT('',(-0.614349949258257,0.0842150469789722,-0.2));
#733=CARTESIAN_POINT('',(-0.604088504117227,0.0577700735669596,-0.2));
#734=CARTESIAN_POINT('',(-0.596868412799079,0.0287667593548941,-0.2));
#735=CARTESIAN_POINT('',(-0.592400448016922,-0.00271483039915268,-0.2));
#736=CARTESIAN_POINT('',(-0.591895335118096,-0.0245208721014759,-0.2));
#737=CARTESIAN_POINT('',(-0.591634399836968,-0.0357856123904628,-0.2));
#738=B_SPLINE_CURVE_WITH_KNOTS('',3,(#723,#724,#725,#726,#727,#728,#729,#730,#731,#732,#733,
#734,#735,#736,#737),.UNSPECIFIED.,.F.,.F.,(4,1,1,1,1,1,1,1,1,1,1,1,4),(0.,0.0902231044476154,
0.174222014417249,0.25444494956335,0.331160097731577,0.406319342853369,0.481243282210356,
0.557346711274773,0.636723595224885,0.719561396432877,0.807304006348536,0.900455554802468,1.),.UNSPECIFIED.);
#739=DIRECTION('',(0.,0.,1.));
#740=VECTOR('',#739,1.);
#741=SURFACE_OF_LINEAR_EXTRUSION('',#738,#740);
#742=ORIENTED_EDGE('',*,*,#200,.T.);
#743=ORIENTED_EDGE('',*,*,#718,.F.);
#744=CARTESIAN_POINT('',(-0.791430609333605,0.186264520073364,-0.2));
#745=VERTEX_POINT('',#744);
#746=EDGE_CURVE('E450',#745,#711,#738,.T.);
#747=ORIENTED_EDGE('',*,*,#746,.F.);
#748=DIRECTION('',(0.,0.,1.));
#749=VECTOR('',#748,1.);
#750=CARTESIAN_POINT('',(-0.791430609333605,0.186264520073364,-0.2));
#751=LINE('',#750,#749);
#752=EDGE_CURVE('E333',#745,#199,#751,.T.);
#753=ORIENTED_EDGE('',*,*,#752,.T.);
#754=EDGE_LOOP('',(#742,#743,#747,#753));
#755=FACE_BOUND('',#754,.T.);
#756=ADVANCED_FACE('F441',(#755),#741,.F.);
#757=CARTESIAN_POINT('',(-0.987069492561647,-0.00179335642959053,-0.2));
#758=CARTESIAN_POINT('',(-0.984706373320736,0.00779221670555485,-0.2));
#759=CARTESIAN_POINT('',(-0.980107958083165,0.0264448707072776,-0.2));
#760=CARTESIAN_POINT('',(-0.970640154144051,0.0529798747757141,-0.2));
#761=CARTESIAN_POINT('',(-0.959874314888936,0.0775584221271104,-0.2));
#762=CARTESIAN_POINT('',(-0.946707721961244,0.0995949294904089,-0.2));
#763=CARTESIAN_POINT('',(-0.932374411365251,0.11962144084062,-0.2));
#764=CARTESIAN_POINT('',(-0.916209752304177,0.136971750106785,-0.2));
#765=CARTESIAN_POINT('',(-0.898567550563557,0.151933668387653,-0.2));
#766=CARTESIAN_POINT('',(-0.879584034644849,0.164308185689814,-0.2));
#767=CARTESIAN_POINT('',(-0.859310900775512,0.17439320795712,-0.2));
#768=CARTESIAN_POINT('',(-0.837655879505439,0.181067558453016,-0.2));
#769=CARTESIAN_POINT('',(-0.814917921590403,0.185425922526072,-0.2));
#770=CARTESIAN_POINT('',(-0.799358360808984,0.185981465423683,-0.2));
#771=CARTESIAN_POINT('',(-0.791430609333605,0.186264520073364,-0.2));
#772=B_SPLINE_CURVE_WITH_KNOTS('',3,(#757,#758,#759,#760,#761,#762,#763,#764,#765,#766,#767,
#768,#769,#770,#771),.UNSPECIFIED.,.F.,.F.,(4,1,1,1,1,1,1,1,1,1,1,1,4),(0.,0.100258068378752,
0.195093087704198,0.285925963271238,0.37244127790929,0.455447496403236,0.535743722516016,
0.612742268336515,0.689936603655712,0.765509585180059,0.842003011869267,0.919498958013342,1.),.UNSPECIFIED.);
#773=DIRECTION('',(0.,0.,1.));
#774=VECTOR('',#773,1.);
#775=SURFACE_OF_LINEAR_EXTRUSION('',#772,#774);
#776=ORIENTED_EDGE('',*,*,#220,.T.);
#777=ORIENTED_EDGE('',*,*,#752,.F.);
#778=CARTESIAN_POINT('',(-0.987069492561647,-0.00179335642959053,-0.2));
#779=VERTEX_POINT('',#778);
#780=EDGE_CURVE('E456',#779,#745,#772,.T.);
#781=ORIENTED_EDGE('',*,*,#780,.F.);
#782=DIRECTION('',(0.,0.,1.));
#783=VECTOR('',#782,1.);
#784=CARTESIAN_POINT('',(-0.987069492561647,-0.00179335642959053,-0.2));
#785=LINE('',#784,#783);
#786=EDGE_CURVE('E331',#779,#219,#785,.T.);
#787=ORIENTED_EDGE('',*,*,#786,.T.);
#788=EDGE_LOOP('',(#776,#777,#781,#787));
#789=FACE_BOUND('',#788,.T.);
#790=ADVANCED_FACE('F446',(#789),#775,.F.);
#791=CARTESIAN_POINT('',(-1.22134705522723,-0.00179335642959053,-0.2));
#792=DIRECTION('',(0.,-1.,0.));
#793=DIRECTION('',(0.,0.,-1.));
#794=AXIS2_PLACEMENT_3D('',#791,#792,#793);
#795=PLANE('',#794);
#796=ORIENTED_EDGE('',*,*,#228,.T.);
#797=ORIENTED_EDGE('',*,*,#786,.F.);
#798=DIRECTION('',(1.,0.,0.));
#799=VECTOR('',#798,1.);
#800=CARTESIAN_POINT('',(-1.22134705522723,-0.00179335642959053,-0.2));
#801=LINE('',#800,#799);
#802=CARTESIAN_POINT('',(-1.22134705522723,-0.00179335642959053,-0.2));
#803=VERTEX_POINT('',#802);
#804=EDGE_CURVE('E675',#803,#779,#801,.T.);
#805=ORIENTED_EDGE('',*,*,#804,.F.);
#806=DIRECTION('',(0.,0.,1.));
#807=VECTOR('',#806,1.);
#808=CARTESIAN_POINT('',(-1.22134705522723,-0.00179335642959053,-0.2));
#809=LINE('',#808,#807);
#810=EDGE_CURVE('E329',#803,#227,#809,.T.);
#811=ORIENTED_EDGE('',*,*,#810,.T.);
#812=EDGE_LOOP('',(#796,#797,#805,#811));
#813=FACE_BOUND('',#812,.T.);
#814=ADVANCED_FACE('F532',(#813),#795,.F.);
#815=CARTESIAN_POINT('',(-0.791430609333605,0.412471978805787,-0.2));
#816=CARTESIAN_POINT('',(-0.809815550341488,0.411979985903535,-0.2));
#817=CARTESIAN_POINT('',(-0.84585461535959,0.411015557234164,-0.2));
#818=CARTESIAN_POINT('',(-0.89823459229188,0.401332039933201,-0.2));
#819=CARTESIAN_POINT('',(-0.947698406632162,0.386255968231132,-0.2));
#820=CARTESIAN_POINT('',(-0.9939569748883,0.364758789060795,-0.2));
#821=CARTESIAN_POINT('',(-1.03686547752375,0.337635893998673,-0.2));
#822=CARTESIAN_POINT('',(-1.07592155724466,0.304635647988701,-0.2));
#823=CARTESIAN_POINT('',(-1.11111207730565,0.266190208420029,-0.2));
#824=CARTESIAN_POINT('',(-1.14213327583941,0.222142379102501,-0.2));
#825=CARTESIAN_POINT('',(-1.16907351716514,0.173106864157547,-0.2));
#826=CARTESIAN_POINT('',(-1.19125174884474,0.11907771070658,-0.2));
#827=CARTESIAN_POINT('',(-1.2092538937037,0.060457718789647,-0.2));
#828=CARTESIAN_POINT('',(-1.2172439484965,0.0193279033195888,-0.2));
#829=CARTESIAN_POINT('',(-1.22134705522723,-0.00179335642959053,-0.2));
#830=B_SPLINE_CURVE_WITH_KNOTS('',3,(#815,#816,#817,#818,#819,#820,#821,#822,#823,#824,#825,
#826,#827,#828,#829),.UNSPECIFIED.,.F.,.F.,(4,1,1,1,1,1,1,1,1,1,1,1,4),(0.,0.0840057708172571,
0.164672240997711,0.242738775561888,0.319972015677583,0.397234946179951,0.474233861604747,
0.553133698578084,0.634960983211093,0.720060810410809,0.808478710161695,0.901648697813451,1.),.UNSPECIFIED.);
#831=DIRECTION('',(0.,0.,1.));
#832=VECTOR('',#831,1.);
#833=SURFACE_OF_LINEAR_EXTRUSION('',#830,#832);
#834=ORIENTED_EDGE('',*,*,#248,.T.);
#835=ORIENTED_EDGE('',*,*,#810,.F.);
#836=CARTESIAN_POINT('',(-0.791430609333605,0.412471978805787,-0.2));
#837=VERTEX_POINT('',#836);
#838=EDGE_CURVE('E482',#837,#803,#830,.T.);
#839=ORIENTED_EDGE('',*,*,#838,.F.);
#840=DIRECTION('',(0.,0.,1.));
#841=VECTOR('',#840,1.);
#842=CARTESIAN_POINT('',(-0.791430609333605,0.412471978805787,-0.2));
#843=LINE('',#842,#841);
#844=EDGE_CURVE('E327',#837,#247,#843,.T.);
#845=ORIENTED_EDGE('',*,*,#844,.T.);
#846=EDGE_LOOP('',(#834,#835,#839,#845));
#847=FACE_BOUND('',#846,.T.);
#848=ADVANCED_FACE('F498',(#847),#833,.F.);
#849=CARTESIAN_POINT('',(-0.357356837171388,-0.0357856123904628,-0.2));
#850=CARTESIAN_POINT('',(-0.357466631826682,-0.0241235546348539,-0.2));
#851=CARTESIAN_POINT('',(-0.357681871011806,-0.00126149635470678,-0.2));
#852=CARTESIAN_POINT('',(-0.360289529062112,0.032352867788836,-0.2));
#853=CARTESIAN_POINT('',(-0.364051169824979,0.0646228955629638,-0.2));
#854=CARTESIAN_POINT('',(-0.369694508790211,0.0955789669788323,-0.2));
#855=CARTESIAN_POINT('',(-0.377065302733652,0.125197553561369,-0.2));
#856=CARTESIAN_POINT('',(-0.385876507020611,0.153613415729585,-0.2));
#857=CARTESIAN_POINT('',(-0.396039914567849,0.180821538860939,-0.2));
#858=CARTESIAN_POINT('',(-0.408080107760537,0.206523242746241,-0.2));
#859=CARTESIAN_POINT('',(-0.421618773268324,0.230834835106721,-0.2));
#860=CARTESIAN_POINT('',(-0.436397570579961,0.253845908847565,-0.2));
#861=CARTESIAN_POINT('',(-0.453006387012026,0.275210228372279,-0.2));
#862=CARTESIAN_POINT('',(-0.470729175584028,0.295319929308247,-0.2));
#863=CARTESIAN_POINT('',(-0.490200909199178,0.313720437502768,-0.2));
#864=CARTESIAN_POINT('',(-0.511024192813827,0.330554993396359,-0.2));
#865=CARTESIAN_POINT('',(-0.53315359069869,0.346164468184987,-0.2));
#866=CARTESIAN_POINT('',(-0.556890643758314,0.35994506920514,-0.2));
#867=CARTESIAN_POINT('',(-0.581878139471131,0.372572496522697,-0.2));
#868=CARTESIAN_POINT('',(-0.608264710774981,0.383198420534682,-0.2));
#869=CARTESIAN_POINT('',(-0.635774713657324,0.392337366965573,-0.2));
#870=CARTESIAN_POINT('',(-0.664568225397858,0.399609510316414,-0.2));
#871=CARTESIAN_POINT('',(-0.694518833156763,0.405490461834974,-0.2));
#872=CARTESIAN_POINT('',(-0.725796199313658,0.409629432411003,-0.2));
#873=CARTESIAN_POINT('',(-0.758212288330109,0.412113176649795,-0.2));
#874=CARTESIAN_POINT('',(-0.780258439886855,0.412351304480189,-0.2));
#875=CARTESIAN_POINT('',(-0.791430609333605,0.412471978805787,-0.2));
#876=B_SPLINE_CURVE_WITH_KNOTS('',3,(#849,#850,#851,#852,#853,#854,#855,#856,#857,#858,#859,
#860,#861,#862,#863,#864,#865,#866,#867,#868,#869,#870,#871,#872,#873,#874,#875),.UNSPECIFIED.,
.F.,.F.,(4,1,1,1,1,1,1,1,1,1,1,1,1,1,1,1,1,1,1,1,1,1,1,1,4),(0.,0.0493032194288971,
0.0966530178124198,0.142486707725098,0.186636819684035,0.229608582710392,0.271475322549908,
0.312384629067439,0.352325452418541,0.391363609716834,0.429990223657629,0.467841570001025,
0.505685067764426,0.543233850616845,0.580972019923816,0.618840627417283,0.657622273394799,
0.696931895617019,0.737130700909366,0.777789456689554,0.819424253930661,0.862622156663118,
0.906789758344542,0.952764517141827,1.),.UNSPECIFIED.);
#877=DIRECTION('',(0.,0.,1.));
#878=VECTOR('',#877,1.);
#879=SURFACE_OF_LINEAR_EXTRUSION('',#876,#878);
#880=ORIENTED_EDGE('',*,*,#280,.T.);
#881=ORIENTED_EDGE('',*,*,#844,.F.);
#882=CARTESIAN_POINT('',(-0.357356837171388,-0.0357856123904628,-0.2));
#883=VERTEX_POINT('',#882);
#884=EDGE_CURVE('E481',#883,#837,#876,.T.);
#885=ORIENTED_EDGE('',*,*,#884,.F.);
#886=DIRECTION('',(0.,0.,1.));
#887=VECTOR('',#886,1.);
#888=CARTESIAN_POINT('',(-0.357356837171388,-0.0357856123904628,-0.2));
#889=LINE('',#888,#887);
#890=EDGE_CURVE('E325',#883,#279,#889,.T.);
#891=ORIENTED_EDGE('',*,*,#890,.T.);
#892=EDGE_LOOP('',(#880,#881,#885,#891));
#893=FACE_BOUND('',#892,.T.);
#894=ADVANCED_FACE('F495',(#893),#879,.F.);
#895=CARTESIAN_POINT('',(-0.357356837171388,-0.364948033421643,-0.2));
#896=DIRECTION('',(1.,0.,0.));
#897=DIRECTION('',(0.,0.,-1.));
#898=AXIS2_PLACEMENT_3D('',#895,#896,#897);
#899=PLANE('',#898);
#900=ORIENTED_EDGE('',*,*,#286,.T.);
#901=ORIENTED_EDGE('',*,*,#890,.F.);
#902=DIRECTION('',(0.,1.,0.));
#903=VECTOR('',#902,1.);
#904=CARTESIAN_POINT('',(-0.357356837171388,-0.364948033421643,-0.2));
#905=LINE('',#904,#903);
#906=CARTESIAN_POINT('',(-0.357356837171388,-0.364948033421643,-0.2));
#907=VERTEX_POINT('',#906);
#908=EDGE_CURVE('E180',#907,#883,#905,.T.);
#909=ORIENTED_EDGE('',*,*,#908,.F.);
#910=DIRECTION('',(0.,0.,1.));
#911=VECTOR('',#910,1.);
#912=CARTESIAN_POINT('',(-0.357356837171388,-0.364948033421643,-0.2));
#913=LINE('',#912,#911);
#914=EDGE_CURVE('E171',#907,#103,#913,.T.);
#915=ORIENTED_EDGE('',*,*,#914,.T.);
#916=EDGE_LOOP('',(#900,#901,#909,#915));
#917=FACE_BOUND('',#916,.T.);
#918=ADVANCED_FACE('F478',(#917),#899,.F.);
#919=CARTESIAN_POINT('',(-0.791430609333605,-0.812471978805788,-0.2));
#920=CARTESIAN_POINT('',(-0.780258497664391,-0.812351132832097,-0.2));
#921=CARTESIAN_POINT('',(-0.758212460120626,-0.812112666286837,-0.2));
#922=CARTESIAN_POINT('',(-0.725795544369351,-0.809631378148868,-0.2));
#923=CARTESIAN_POINT('',(-0.694521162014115,-0.805483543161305,-0.2));
#924=CARTESIAN_POINT('',(-0.66455986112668,-0.799634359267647,-0.2));
#925=CARTESIAN_POINT('',(-0.635828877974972,-0.792255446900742,-0.2));
#926=CARTESIAN_POINT('',(-0.608205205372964,-0.783533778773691,-0.2));
#927=CARTESIAN_POINT('',(-0.581954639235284,-0.772736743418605,-0.2));
#928=CARTESIAN_POINT('',(-0.556822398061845,-0.760492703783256,-0.2));
#929=CARTESIAN_POINT('',(-0.53316239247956,-0.746634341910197,-0.2));
#930=CARTESIAN_POINT('',(-0.511024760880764,-0.731046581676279,-0.2));
#931=CARTESIAN_POINT('',(-0.490189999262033,-0.714218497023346,-0.2));
#932=CARTESIAN_POINT('',(-0.470816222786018,-0.695812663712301,-0.2));
#933=CARTESIAN_POINT('',(-0.452923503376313,-0.675936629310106,-0.2));
#934=CARTESIAN_POINT('',(-0.436410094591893,-0.65456836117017,-0.2));
#935=CARTESIAN_POINT('',(-0.421615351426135,-0.631571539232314,-0.2));
#936=CARTESIAN_POINT('',(-0.408081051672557,-0.607256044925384,-0.2));
#937=CARTESIAN_POINT('',(-0.396039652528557,-0.58155541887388,-0.2));
#938=CARTESIAN_POINT('',(-0.385876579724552,-0.55434699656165,-0.2));
#939=CARTESIAN_POINT('',(-0.377065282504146,-0.525931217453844,-0.2));
#940=CARTESIAN_POINT('',(-0.36969451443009,-0.496312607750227,-0.2));
#941=CARTESIAN_POINT('',(-0.364051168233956,-0.465356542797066,-0.2));
#942=CARTESIAN_POINT('',(-0.360289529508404,-0.433086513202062,-0.2));
#943=CARTESIAN_POINT('',(-0.357681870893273,-0.39947214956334,-0.2));
#944=CARTESIAN_POINT('',(-0.357466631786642,-0.376610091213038,-0.2));
#945=CARTESIAN_POINT('',(-0.357356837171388,-0.364948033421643,-0.2));
#946=B_SPLINE_CURVE_WITH_KNOTS('',3,(#919,#920,#921,#922,#923,#924,#925,#926,#927,#928,#929,
#930,#931,#932,#933,#934,#935,#936,#937,#938,#939,#940,#941,#942,#943,#944,#945),.UNSPECIFIED.,
.F.,.F.,(4,1,1,1,1,1,1,1,1,1,1,1,1,1,1,1,1,1,1,1,1,1,1,1,4),(0.,0.04725989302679,
0.0932584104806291,0.137448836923,0.180669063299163,0.222325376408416,0.262898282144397,
0.303117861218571,0.342294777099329,0.381096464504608,0.418984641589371,0.456742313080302,
0.494310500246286,0.531916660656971,0.569787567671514,0.608434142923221,0.647492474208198,
0.687453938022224,0.728384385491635,0.770272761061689,0.813266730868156,0.85743965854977,
0.903297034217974,0.950671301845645,1.),.UNSPECIFIED.);
#947=DIRECTION('',(0.,0.,1.));
#948=VECTOR('',#947,1.);
#949=SURFACE_OF_LINEAR_EXTRUSION('',#946,#948);
#950=ORIENTED_EDGE('',*,*,#104,.T.);
#951=ORIENTED_EDGE('',*,*,#914,.F.);
#952=EDGE_CURVE('E175',#591,#907,#946,.T.);
#953=ORIENTED_EDGE('',*,*,#952,.F.);
#954=ORIENTED_EDGE('',*,*,#592,.T.);
#955=EDGE_LOOP('',(#950,#951,#953,#954));
#956=FACE_BOUND('',#955,.T.);
#957=ADVANCED_FACE('F176',(#956),#949,.F.);
#958=CARTESIAN_POINT('',(-1.08639720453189,-0.691733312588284,-0.2));
#959=DIRECTION('',(0.,0.,-1.));
#960=DIRECTION('',(-1.,0.,0.));
#961=AXIS2_PLACEMENT_3D('',#958,#959,#960);
#962=PLANE('',#961);
#963=ORIENTED_EDGE('',*,*,#596,.T.);
#964=ORIENTED_EDGE('',*,*,#952,.T.);
#965=ORIENTED_EDGE('',*,*,#908,.T.);
#966=ORIENTED_EDGE('',*,*,#884,.T.);
#967=ORIENTED_EDGE('',*,*,#838,.T.);
#968=ORIENTED_EDGE('',*,*,#804,.T.);
#969=ORIENTED_EDGE('',*,*,#780,.T.);
#970=ORIENTED_EDGE('',*,*,#746,.T.);
#971=ORIENTED_EDGE('',*,*,#712,.T.);
#972=ORIENTED_EDGE('',*,*,#688,.T.);
#973=ORIENTED_EDGE('',*,*,#654,.T.);
#974=ORIENTED_EDGE('',*,*,#620,.T.);
#975=EDGE_LOOP('',(#963,#964,#965,#966,#967,#968,#969,#970,#971,#972,#973,#974));
#976=FACE_BOUND('',#975,.T.);
#977=ADVANCED_FACE('F182',(#976),#962,.F.);
#978=CLOSED_SHELL('',(#46,#66,#352,#369,#381,#413,#437,#461,#485,#509,#533,#550,#565,#606,#630,
#664,#698,#722,#756,#790,#814,#848,#894,#918,#957,#977));
#979=MANIFOLD_SOLID_BREP('B2',#978);
#980=ADVANCED_BREP_SHAPE_REPRESENTATION('',(#18,#979),#14);
#981=SHAPE_DEFINITION_REPRESENTATION(#9,#980);
ENDSEC;
END-ISO-10303-21;
